VERSION 5.8 ;
BUSBITCHARS "[]" ;
DIVIDERCHAR "/" ;
UNITS
    DATABASE MICRONS 1000 ;
END UNITS

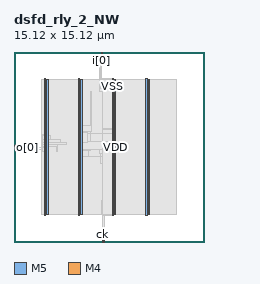
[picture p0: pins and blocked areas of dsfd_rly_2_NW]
MACRO dsfd_rly_2_NW
  FOREIGN dsfd_rly_2_NW 0 0 ;
  CLASS BLOCK ;
  SIZE 15.12 BY 15.12 ;
  PIN ck
    DIRECTION INPUT ;
    USE SIGNAL ;
    PORT
      LAYER M5 ;
        RECT  7.056 0 7.08 0.084 ;
    END
  END ck
  PIN i[0]
    DIRECTION INPUT ;
    USE SIGNAL ;
    PORT
      LAYER M5 ;
        RECT  6.96 15.036 6.984 15.12 ;
    END
  END i[0]
  PIN i[1]
    DIRECTION INPUT ;
    USE SIGNAL ;
    PORT
      LAYER M5 ;
        RECT  7.056 15.036 7.08 15.12 ;
    END
  END i[1]
  PIN o[0]
    DIRECTION OUTPUT ;
    USE SIGNAL ;
    PORT
      LAYER M4 ;
        RECT  0 7.536 0.084 7.56 ;
    END
  END o[0]
  PIN o[1]
    DIRECTION OUTPUT ;
    USE SIGNAL ;
    PORT
      LAYER M4 ;
        RECT  0 7.632 0.084 7.656 ;
    END
  END o[1]
  PIN rs
    DIRECTION INPUT ;
    USE SIGNAL ;
    PORT
      LAYER M5 ;
        RECT  7.152 0 7.176 0.084 ;
    END
  END rs
  PIN VDD
    DIRECTION INOUT ;
    USE POWER ;
    PORT
      LAYER M5 ;
        RECT  10.692 2.151 10.812 12.969 ;
        RECT  7.992 2.151 8.112 12.969 ;
        RECT  5.292 2.151 5.412 12.969 ;
        RECT  2.592 2.151 2.712 12.969 ;
    END
  END VDD
  PIN VSS
    DIRECTION INOUT ;
    USE GROUND ;
    PORT
      LAYER M5 ;
        RECT  10.5 2.137 10.62 12.983 ;
        RECT  7.8 2.137 7.92 12.983 ;
        RECT  5.1 2.137 5.22 12.983 ;
        RECT  2.4 2.137 2.52 12.983 ;
    END
  END VSS
  OBS
    LAYER RVTN ;
     RECT  2.16 2.16 12.96 2.295 ;
     RECT  2.16 2.565 12.96 2.835 ;
     RECT  2.16 3.105 12.96 3.375 ;
     RECT  2.16 3.645 12.96 3.915 ;
     RECT  2.16 4.185 12.96 4.455 ;
     RECT  2.16 4.725 12.96 4.995 ;
     RECT  2.16 5.265 12.96 5.535 ;
     RECT  2.16 5.805 12.96 6.075 ;
     RECT  2.16 6.345 12.96 6.615 ;
     RECT  2.16 6.885 12.96 7.155 ;
     RECT  2.16 7.425 12.96 7.695 ;
     RECT  2.16 7.965 12.96 8.235 ;
     RECT  2.16 8.505 12.96 8.775 ;
     RECT  2.16 9.045 12.96 9.315 ;
     RECT  2.16 9.585 12.96 9.855 ;
     RECT  2.16 10.125 12.96 10.395 ;
     RECT  2.16 10.665 12.96 10.935 ;
     RECT  2.16 11.205 12.96 11.475 ;
     RECT  2.16 11.745 12.96 12.015 ;
     RECT  2.16 12.285 12.96 12.555 ;
     RECT  2.16 12.825 12.96 12.96 ;
    LAYER RVTP ;
     RECT  2.16 2.295 12.96 2.565 ;
     RECT  2.16 2.835 12.96 3.105 ;
     RECT  2.16 3.375 12.96 3.645 ;
     RECT  2.16 3.915 12.96 4.185 ;
     RECT  2.16 4.455 12.96 4.725 ;
     RECT  2.16 4.995 12.96 5.265 ;
     RECT  2.16 5.535 12.96 5.805 ;
     RECT  2.16 6.075 12.96 6.345 ;
     RECT  2.16 6.615 12.96 6.885 ;
     RECT  2.16 7.155 12.96 7.425 ;
     RECT  2.16 7.695 12.96 7.965 ;
     RECT  2.16 8.235 12.96 8.505 ;
     RECT  2.16 8.775 12.96 9.045 ;
     RECT  2.16 9.315 12.96 9.585 ;
     RECT  2.16 9.855 12.96 10.125 ;
     RECT  2.16 10.395 12.96 10.665 ;
     RECT  2.16 10.935 12.96 11.205 ;
     RECT  2.16 11.475 12.96 11.745 ;
     RECT  2.16 12.015 12.96 12.285 ;
     RECT  2.16 12.555 12.96 12.825 ;
    LAYER M1 ;
     RECT  2.16 2.151 12.96 12.969 ;
    LAYER M2 ;
     RECT  0.103 7.326 2.16 7.344 ;
     RECT  2.16 2.151 12.96 12.969 ;
    LAYER M3 ;
     RECT  2.415 2.143 2.505 2.413 ;
     RECT  5.115 2.143 5.205 2.413 ;
     RECT  7.815 2.143 7.905 2.413 ;
     RECT  10.515 2.143 10.605 2.413 ;
     RECT  6.984 2.251 7.002 3.335 ;
     RECT  7.815 2.413 8.097 3.451 ;
     RECT  7.128 3.451 8.097 6.241 ;
     RECT  5.115 2.413 5.397 6.811 ;
     RECT  6.912 6.241 8.097 7.051 ;
     RECT  2.415 2.413 2.697 7.231 ;
     RECT  5.115 6.811 5.958 7.321 ;
     RECT  5.115 7.321 6.102 7.357 ;
     RECT  6.84 7.051 8.097 7.357 ;
     RECT  2.304 7.231 2.697 7.591 ;
     RECT  3.42 7.195 3.438 7.591 ;
     RECT  0.108 7.321 0.126 7.661 ;
     RECT  2.304 7.591 3.438 7.771 ;
     RECT  2.304 7.771 4.158 7.889 ;
     RECT  5.115 7.357 8.097 7.961 ;
     RECT  2.304 7.889 3.69 8.159 ;
     RECT  2.304 8.159 2.898 8.501 ;
     RECT  2.304 8.501 2.697 8.537 ;
     RECT  5.115 7.961 6.102 8.806 ;
     RECT  7.02 7.961 8.097 8.969 ;
     RECT  7.056 8.969 8.097 9.041 ;
     RECT  5.115 8.806 6.138 9.239 ;
     RECT  6.12 9.239 6.138 11.939 ;
     RECT  7.056 9.041 7.074 11.947 ;
     RECT  6.84 11.947 7.074 12.209 ;
     RECT  6.84 12.209 6.894 12.557 ;
     RECT  2.415 8.537 2.697 12.707 ;
     RECT  5.115 9.239 5.397 12.707 ;
     RECT  7.815 9.041 8.097 12.707 ;
     RECT  10.515 2.413 10.797 12.707 ;
     RECT  2.415 12.707 2.505 12.977 ;
     RECT  5.115 12.707 5.205 12.977 ;
     RECT  7.815 12.707 7.905 12.977 ;
     RECT  10.515 12.707 10.605 12.977 ;
     RECT  6.84 12.557 6.858 14.285 ;
    LAYER M4 ;
     RECT  0.06 7.536 0.137 7.656 ;
     RECT  0.137 7.536 2.408 7.56 ;
     RECT  2.408 2.148 2.512 12.972 ;
     RECT  2.512 2.418 2.704 12.702 ;
     RECT  5.108 2.148 5.212 12.972 ;
     RECT  5.212 2.418 5.404 12.702 ;
     RECT  5.404 7.968 5.843 8.664 ;
     RECT  5.404 6.816 7.037 6.84 ;
     RECT  6.829 14.256 7.091 14.28 ;
     RECT  7.037 6.816 7.333 7.464 ;
     RECT  6.973 2.256 7.808 2.28 ;
     RECT  7.333 6.576 7.808 7.464 ;
     RECT  5.843 8.64 7.808 8.664 ;
     RECT  6.865 12.528 7.808 12.552 ;
     RECT  7.808 2.148 7.912 12.972 ;
     RECT  7.912 2.418 8.104 12.702 ;
     RECT  10.508 2.148 10.612 12.972 ;
     RECT  10.612 2.418 10.804 12.702 ;
    LAYER M5 ;
     RECT  7.056 0.016 7.176 2.137 ;
     RECT  2.4 2.137 2.52 2.151 ;
     RECT  5.1 2.137 5.22 2.151 ;
     RECT  7.056 2.137 7.92 2.151 ;
     RECT  10.5 2.137 10.62 2.151 ;
     RECT  7.056 2.151 8.112 7.475 ;
     RECT  5.1 2.151 5.412 7.957 ;
     RECT  5.1 7.957 5.832 8.675 ;
     RECT  7.8 7.475 8.112 12.517 ;
     RECT  2.4 2.151 2.712 12.969 ;
     RECT  5.1 8.675 5.412 12.969 ;
     RECT  6.96 12.517 8.112 12.969 ;
     RECT  10.5 2.151 10.812 12.969 ;
     RECT  2.4 12.969 2.52 12.983 ;
     RECT  5.1 12.969 5.22 12.983 ;
     RECT  6.96 12.969 7.92 12.983 ;
     RECT  10.5 12.969 10.62 12.983 ;
     RECT  6.96 12.983 6.984 14.245 ;
     RECT  6.96 14.245 7.08 15.056 ;
  END
END dsfd_rly_2_NW
END LIBRARY
